VERSION 5.7 ;
  NOWIREEXTENSIONATPIN ON ;
  DIVIDERCHAR "/" ;
  BUSBITCHARS "[]" ;
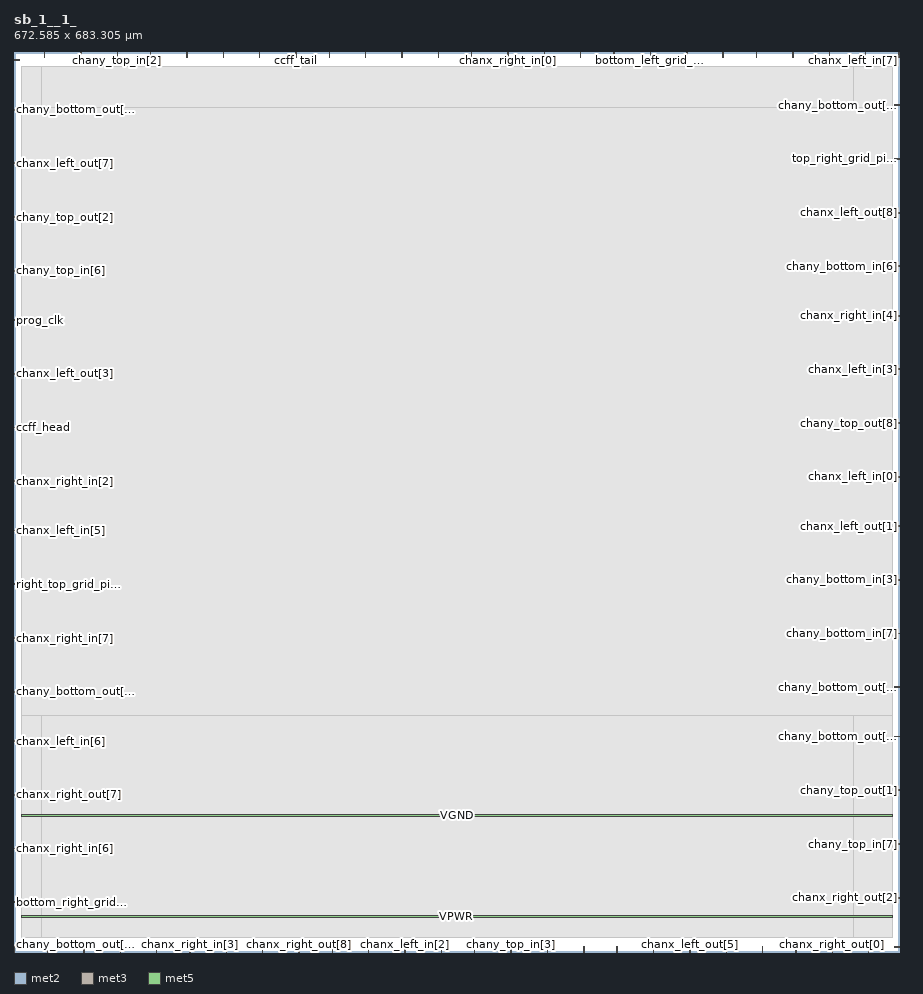
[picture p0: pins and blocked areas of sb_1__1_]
MACRO sb_1__1_
  CLASS BLOCK ;
  FOREIGN sb_1__1_ ;
  ORIGIN 0.000 0.000 ;
  SIZE 672.585 BY 683.305 ;
  PIN bottom_left_grid_pin_13_
    DIRECTION INPUT ;
    PORT
      LAYER met2 ;
        RECT 483.090 679.305 483.370 683.305 ;
    END
  END bottom_left_grid_pin_13_
  PIN bottom_right_grid_pin_11_
    DIRECTION INPUT ;
    PORT
      LAYER met3 ;
        RECT 0.000 37.440 4.000 38.040 ;
    END
  END bottom_right_grid_pin_11_
  PIN ccff_head
    DIRECTION INPUT ;
    PORT
      LAYER met3 ;
        RECT 0.000 397.840 4.000 398.440 ;
    END
  END ccff_head
  PIN ccff_tail
    DIRECTION OUTPUT TRISTATE ;
    PORT
      LAYER met2 ;
        RECT 213.990 679.305 214.270 683.305 ;
    END
  END ccff_tail
  PIN chanx_left_in[0]
    DIRECTION INPUT ;
    PORT
      LAYER met3 ;
        RECT 668.585 360.440 672.585 361.040 ;
    END
  END chanx_left_in[0]
  PIN chanx_left_in[1]
    DIRECTION INPUT ;
    PORT
      LAYER met2 ;
        RECT 241.590 0.000 241.870 4.000 ;
    END
  END chanx_left_in[1]
  PIN chanx_left_in[2]
    DIRECTION INPUT ;
    PORT
      LAYER met2 ;
        RECT 296.790 0.000 297.070 4.000 ;
    END
  END chanx_left_in[2]
  PIN chanx_left_in[3]
    DIRECTION INPUT ;
    PORT
      LAYER met3 ;
        RECT 668.585 442.040 672.585 442.640 ;
    END
  END chanx_left_in[3]
  PIN chanx_left_in[4]
    DIRECTION INPUT ;
    PORT
      LAYER met2 ;
        RECT 510.690 679.305 510.970 683.305 ;
    END
  END chanx_left_in[4]
  PIN chanx_left_in[5]
    DIRECTION INPUT ;
    PORT
      LAYER met3 ;
        RECT 0.000 319.640 4.000 320.240 ;
    END
  END chanx_left_in[5]
  PIN chanx_left_in[6]
    DIRECTION INPUT ;
    PORT
      LAYER met3 ;
        RECT 0.000 159.840 4.000 160.440 ;
    END
  END chanx_left_in[6]
  PIN chanx_left_in[7]
    DIRECTION INPUT ;
    PORT
      LAYER met2 ;
        RECT 646.390 679.305 646.670 683.305 ;
    END
  END chanx_left_in[7]
  PIN chanx_left_in[8]
    DIRECTION INPUT ;
    PORT
      LAYER met2 ;
        RECT 324.390 0.000 324.670 4.000 ;
    END
  END chanx_left_in[8]
  PIN chanx_left_out[0]
    DIRECTION OUTPUT TRISTATE ;
    PORT
      LAYER met2 ;
        RECT 347.390 679.305 347.670 683.305 ;
    END
  END chanx_left_out[0]
  PIN chanx_left_out[1]
    DIRECTION OUTPUT TRISTATE ;
    PORT
      LAYER met3 ;
        RECT 668.585 323.040 672.585 323.640 ;
    END
  END chanx_left_out[1]
  PIN chanx_left_out[2]
    DIRECTION OUTPUT TRISTATE ;
    PORT
      LAYER met2 ;
        RECT 52.990 0.000 53.270 4.000 ;
    END
  END chanx_left_out[2]
  PIN chanx_left_out[3]
    DIRECTION OUTPUT TRISTATE ;
    PORT
      LAYER met3 ;
        RECT 0.000 438.640 4.000 439.240 ;
    END
  END chanx_left_out[3]
  PIN chanx_left_out[4]
    DIRECTION OUTPUT TRISTATE ;
    PORT
      LAYER met2 ;
        RECT 538.290 679.305 538.570 683.305 ;
    END
  END chanx_left_out[4]
  PIN chanx_left_out[5]
    DIRECTION OUTPUT TRISTATE ;
    PORT
      LAYER met2 ;
        RECT 512.990 0.000 513.270 4.000 ;
    END
  END chanx_left_out[5]
  PIN chanx_left_out[6]
    DIRECTION OUTPUT TRISTATE ;
    PORT
      LAYER met3 ;
        RECT 668.585 3.440 672.585 4.040 ;
    END
  END chanx_left_out[6]
  PIN chanx_left_out[7]
    DIRECTION OUTPUT TRISTATE ;
    PORT
      LAYER met3 ;
        RECT 0.000 598.440 4.000 599.040 ;
    END
  END chanx_left_out[7]
  PIN chanx_left_out[8]
    DIRECTION OUTPUT TRISTATE ;
    PORT
      LAYER met3 ;
        RECT 668.585 561.040 672.585 561.640 ;
    END
  END chanx_left_out[8]
  PIN chanx_right_in[0]
    DIRECTION INPUT ;
    PORT
      LAYER met2 ;
        RECT 374.990 679.305 375.270 683.305 ;
    END
  END chanx_right_in[0]
  PIN chanx_right_in[1]
    DIRECTION INPUT ;
    PORT
      LAYER met2 ;
        RECT 404.890 0.000 405.170 4.000 ;
    END
  END chanx_right_in[1]
  PIN chanx_right_in[2]
    DIRECTION INPUT ;
    PORT
      LAYER met3 ;
        RECT 0.000 357.040 4.000 357.640 ;
    END
  END chanx_right_in[2]
  PIN chanx_right_in[3]
    DIRECTION INPUT ;
    PORT
      LAYER met2 ;
        RECT 133.490 0.000 133.770 4.000 ;
    END
  END chanx_right_in[3]
  PIN chanx_right_in[4]
    DIRECTION INPUT ;
    PORT
      LAYER met3 ;
        RECT 668.585 482.840 672.585 483.440 ;
    END
  END chanx_right_in[4]
  PIN chanx_right_in[5]
    DIRECTION INPUT ;
    PORT
      LAYER met2 ;
        RECT 158.790 679.305 159.070 683.305 ;
    END
  END chanx_right_in[5]
  PIN chanx_right_in[6]
    DIRECTION INPUT ;
    PORT
      LAYER met3 ;
        RECT 0.000 78.240 4.000 78.840 ;
    END
  END chanx_right_in[6]
  PIN chanx_right_in[7]
    DIRECTION INPUT ;
    PORT
      LAYER met3 ;
        RECT 0.000 238.040 4.000 238.640 ;
    END
  END chanx_right_in[7]
  PIN chanx_right_in[8]
    DIRECTION INPUT ;
    PORT
      LAYER met2 ;
        RECT 239.290 679.305 239.570 683.305 ;
    END
  END chanx_right_in[8]
  PIN chanx_right_out[0]
    DIRECTION OUTPUT TRISTATE ;
    PORT
      LAYER met2 ;
        RECT 621.090 0.000 621.370 4.000 ;
    END
  END chanx_right_out[0]
  PIN chanx_right_out[1]
    DIRECTION OUTPUT TRISTATE ;
    PORT
      LAYER met2 ;
        RECT 23.090 679.305 23.370 683.305 ;
    END
  END chanx_right_out[1]
  PIN chanx_right_out[2]
    DIRECTION OUTPUT TRISTATE ;
    PORT
      LAYER met3 ;
        RECT 668.585 40.840 672.585 41.440 ;
    END
  END chanx_right_out[2]
  PIN chanx_right_out[3]
    DIRECTION OUTPUT TRISTATE ;
    PORT
      LAYER met2 ;
        RECT 131.190 679.305 131.470 683.305 ;
    END
  END chanx_right_out[3]
  PIN chanx_right_out[4]
    DIRECTION OUTPUT TRISTATE ;
    PORT
      LAYER met2 ;
        RECT 108.190 0.000 108.470 4.000 ;
    END
  END chanx_right_out[4]
  PIN chanx_right_out[5]
    DIRECTION OUTPUT TRISTATE ;
    PORT
      LAYER met2 ;
        RECT 80.590 0.000 80.870 4.000 ;
    END
  END chanx_right_out[5]
  PIN chanx_right_out[6]
    DIRECTION OUTPUT TRISTATE ;
    PORT
      LAYER met2 ;
        RECT 349.690 0.000 349.970 4.000 ;
    END
  END chanx_right_out[6]
  PIN chanx_right_out[7]
    DIRECTION OUTPUT TRISTATE ;
    PORT
      LAYER met3 ;
        RECT 0.000 119.040 4.000 119.640 ;
    END
  END chanx_right_out[7]
  PIN chanx_right_out[8]
    DIRECTION OUTPUT TRISTATE ;
    PORT
      LAYER met2 ;
        RECT 216.290 0.000 216.570 4.000 ;
    END
  END chanx_right_out[8]
  PIN chany_bottom_in[0]
    DIRECTION INPUT ;
    PORT
      LAYER met2 ;
        RECT 161.090 0.000 161.370 4.000 ;
    END
  END chany_bottom_in[0]
  PIN chany_bottom_in[1]
    DIRECTION INPUT ;
    PORT
      LAYER met2 ;
        RECT 563.590 679.305 563.870 683.305 ;
    END
  END chany_bottom_in[1]
  PIN chany_bottom_in[2]
    DIRECTION INPUT ;
    PORT
      LAYER met2 ;
        RECT 25.390 0.000 25.670 4.000 ;
    END
  END chany_bottom_in[2]
  PIN chany_bottom_in[3]
    DIRECTION INPUT ;
    PORT
      LAYER met3 ;
        RECT 668.585 282.240 672.585 282.840 ;
    END
  END chany_bottom_in[3]
  PIN chany_bottom_in[4]
    DIRECTION INPUT ;
    PORT
      LAYER met2 ;
        RECT 568.190 0.000 568.470 4.000 ;
    END
  END chany_bottom_in[4]
  PIN chany_bottom_in[5]
    DIRECTION INPUT ;
    PORT
      LAYER met2 ;
        RECT 455.490 679.305 455.770 683.305 ;
    END
  END chany_bottom_in[5]
  PIN chany_bottom_in[6]
    DIRECTION INPUT ;
    PORT
      LAYER met3 ;
        RECT 668.585 520.240 672.585 520.840 ;
    END
  END chany_bottom_in[6]
  PIN chany_bottom_in[7]
    DIRECTION INPUT ;
    PORT
      LAYER met3 ;
        RECT 668.585 241.440 672.585 242.040 ;
    END
  END chany_bottom_in[7]
  PIN chany_bottom_in[8]
    DIRECTION INPUT ;
    PORT
      LAYER met2 ;
        RECT 648.690 0.000 648.970 4.000 ;
    END
  END chany_bottom_in[8]
  PIN chany_bottom_out[0]
    DIRECTION OUTPUT TRISTATE ;
    PORT
      LAYER met3 ;
        RECT 0.000 197.240 4.000 197.840 ;
    END
  END chany_bottom_out[0]
  PIN chany_bottom_out[1]
    DIRECTION OUTPUT TRISTATE ;
    PORT
      LAYER met2 ;
        RECT 294.490 679.305 294.770 683.305 ;
    END
  END chany_bottom_out[1]
  PIN chany_bottom_out[2]
    DIRECTION OUTPUT TRISTATE ;
    PORT
      LAYER met3 ;
        RECT 668.585 200.640 672.585 201.240 ;
    END
  END chany_bottom_out[2]
  PIN chany_bottom_out[3]
    DIRECTION OUTPUT TRISTATE ;
    PORT
      LAYER met3 ;
        RECT 668.585 163.240 672.585 163.840 ;
    END
  END chany_bottom_out[3]
  PIN chany_bottom_out[4]
    DIRECTION OUTPUT TRISTATE ;
    PORT
      LAYER met2 ;
        RECT 430.190 679.305 430.470 683.305 ;
    END
  END chany_bottom_out[4]
  PIN chany_bottom_out[5]
    DIRECTION OUTPUT TRISTATE ;
    PORT
      LAYER met3 ;
        RECT 668.585 642.640 672.585 643.240 ;
    END
  END chany_bottom_out[5]
  PIN chany_bottom_out[6]
    DIRECTION OUTPUT TRISTATE ;
    PORT
      LAYER met3 ;
        RECT 0.000 639.240 4.000 639.840 ;
    END
  END chany_bottom_out[6]
  PIN chany_bottom_out[7]
    DIRECTION OUTPUT TRISTATE ;
    PORT
      LAYER met2 ;
        RECT 0.090 0.000 0.370 4.000 ;
    END
  END chany_bottom_out[7]
  PIN chany_bottom_out[8]
    DIRECTION OUTPUT TRISTATE ;
    PORT
      LAYER met2 ;
        RECT 50.690 679.305 50.970 683.305 ;
    END
  END chany_bottom_out[8]
  PIN chany_top_in[0]
    DIRECTION INPUT ;
    PORT
      LAYER met2 ;
        RECT 188.690 0.000 188.970 4.000 ;
    END
  END chany_top_in[0]
  PIN chany_top_in[1]
    DIRECTION INPUT ;
    PORT
      LAYER met2 ;
        RECT 103.590 679.305 103.870 683.305 ;
    END
  END chany_top_in[1]
  PIN chany_top_in[2]
    DIRECTION INPUT ;
    PORT
      LAYER met2 ;
        RECT 78.290 679.305 78.570 683.305 ;
    END
  END chany_top_in[2]
  PIN chany_top_in[3]
    DIRECTION INPUT ;
    PORT
      LAYER met2 ;
        RECT 377.290 0.000 377.570 4.000 ;
    END
  END chany_top_in[3]
  PIN chany_top_in[4]
    DIRECTION INPUT ;
    PORT
      LAYER met2 ;
        RECT 485.390 0.000 485.670 4.000 ;
    END
  END chany_top_in[4]
  PIN chany_top_in[5]
    DIRECTION INPUT ;
    PORT
      LAYER met2 ;
        RECT 591.190 679.305 591.470 683.305 ;
    END
  END chany_top_in[5]
  PIN chany_top_in[6]
    DIRECTION INPUT ;
    PORT
      LAYER met3 ;
        RECT 0.000 516.840 4.000 517.440 ;
    END
  END chany_top_in[6]
  PIN chany_top_in[7]
    DIRECTION INPUT ;
    PORT
      LAYER met3 ;
        RECT 668.585 81.640 672.585 82.240 ;
    END
  END chany_top_in[7]
  PIN chany_top_in[8]
    DIRECTION INPUT ;
    PORT
      LAYER met3 ;
        RECT 0.000 676.640 4.000 677.240 ;
    END
  END chany_top_in[8]
  PIN chany_top_out[0]
    DIRECTION OUTPUT TRISTATE ;
    PORT
      LAYER met2 ;
        RECT 402.590 679.305 402.870 683.305 ;
    END
  END chany_top_out[0]
  PIN chany_top_out[1]
    DIRECTION OUTPUT TRISTATE ;
    PORT
      LAYER met3 ;
        RECT 668.585 122.440 672.585 123.040 ;
    END
  END chany_top_out[1]
  PIN chany_top_out[2]
    DIRECTION OUTPUT TRISTATE ;
    PORT
      LAYER met3 ;
        RECT 0.000 557.640 4.000 558.240 ;
    END
  END chany_top_out[2]
  PIN chany_top_out[3]
    DIRECTION OUTPUT TRISTATE ;
    PORT
      LAYER met2 ;
        RECT 432.490 0.000 432.770 4.000 ;
    END
  END chany_top_out[3]
  PIN chany_top_out[4]
    DIRECTION OUTPUT TRISTATE ;
    PORT
      LAYER met2 ;
        RECT 322.090 679.305 322.370 683.305 ;
    END
  END chany_top_out[4]
  PIN chany_top_out[5]
    DIRECTION OUTPUT TRISTATE ;
    PORT
      LAYER met2 ;
        RECT 540.590 0.000 540.870 4.000 ;
    END
  END chany_top_out[5]
  PIN chany_top_out[6]
    DIRECTION OUTPUT TRISTATE ;
    PORT
      LAYER met2 ;
        RECT 457.790 0.000 458.070 4.000 ;
    END
  END chany_top_out[6]
  PIN chany_top_out[7]
    DIRECTION OUTPUT TRISTATE ;
    PORT
      LAYER met2 ;
        RECT 671.690 679.305 671.970 683.305 ;
    END
  END chany_top_out[7]
  PIN chany_top_out[8]
    DIRECTION OUTPUT TRISTATE ;
    PORT
      LAYER met3 ;
        RECT 668.585 401.240 672.585 401.840 ;
    END
  END chany_top_out[8]
  PIN left_bottom_grid_pin_12_
    DIRECTION INPUT ;
    PORT
      LAYER met2 ;
        RECT 266.890 679.305 267.170 683.305 ;
    END
  END left_bottom_grid_pin_12_
  PIN left_top_grid_pin_10_
    DIRECTION INPUT ;
    PORT
      LAYER met2 ;
        RECT 269.190 0.000 269.470 4.000 ;
    END
  END left_top_grid_pin_10_
  PIN pReset
    DIRECTION INPUT ;
    PORT
      LAYER met2 ;
        RECT 618.790 679.305 619.070 683.305 ;
    END
  END pReset
  PIN prog_clk
    DIRECTION INPUT ;
    PORT
      LAYER met3 ;
        RECT 0.000 479.440 4.000 480.040 ;
    END
  END prog_clk
  PIN right_bottom_grid_pin_12_
    DIRECTION INPUT ;
    PORT
      LAYER met2 ;
        RECT 593.490 0.000 593.770 4.000 ;
    END
  END right_bottom_grid_pin_12_
  PIN right_top_grid_pin_10_
    DIRECTION INPUT ;
    PORT
      LAYER met3 ;
        RECT 0.000 278.840 4.000 279.440 ;
    END
  END right_top_grid_pin_10_
  PIN top_left_grid_pin_13_
    DIRECTION INPUT ;
    PORT
      LAYER met2 ;
        RECT 186.390 679.305 186.670 683.305 ;
    END
  END top_left_grid_pin_13_
  PIN top_right_grid_pin_11_
    DIRECTION INPUT ;
    PORT
      LAYER met3 ;
        RECT 668.585 601.840 672.585 602.440 ;
    END
  END top_right_grid_pin_11_
  PIN VPWR
    DIRECTION INPUT ;
    USE POWER ;
    PORT
      LAYER met5 ;
        RECT 5.520 26.490 667.000 28.090 ;
    END
  END VPWR
  PIN VGND
    DIRECTION INPUT ;
    USE GROUND ;
    PORT
      LAYER met5 ;
        RECT 5.520 103.080 667.000 104.680 ;
    END
  END VGND
  OBS
      LAYER li1 ;
        RECT 5.520 10.795 667.000 671.925 ;
      LAYER met1 ;
        RECT 5.520 10.640 667.000 672.080 ;
      LAYER met2 ;
        RECT 21.100 10.640 636.980 672.080 ;
      LAYER met3 ;
        RECT 21.040 10.715 637.040 672.005 ;
      LAYER met4 ;
        RECT 21.040 10.640 637.040 672.080 ;
      LAYER met5 ;
        RECT 5.520 179.670 667.000 640.810 ;
  END
END sb_1__1_
END LIBRARY

